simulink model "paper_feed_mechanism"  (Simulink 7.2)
settings: Solver=FixedStepDiscrete  SolverMode=SingleTasking  StartTime=0  StopTime=5  FixedStep=0.01  RelTol=1e-3
undefined symbols (not defined in the file or in its folder): Enum, ErrorCodeEnum, FeedModeEnum, sigbuilder_block

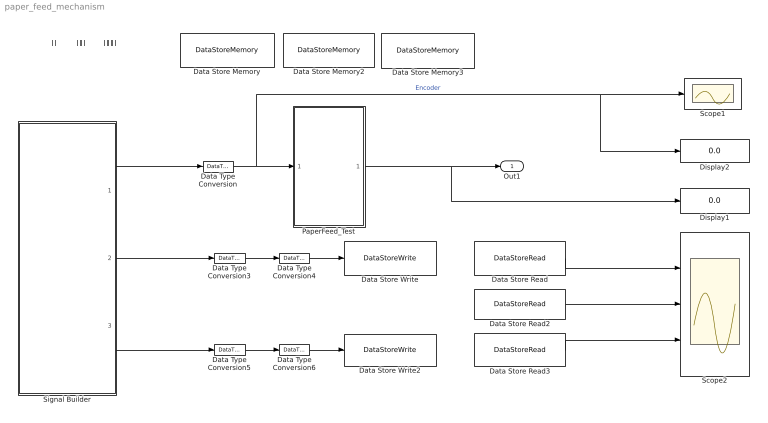
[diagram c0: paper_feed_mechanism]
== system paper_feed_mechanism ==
  note: 単体検証用モデル （給排紙機構）
  Data Store Memory : DataStoreMemory  DataStoreName=ControlMode  ReadBeforeWriteMsg=warning  WriteAfterWriteMsg=warning  WriteAfterReadMsg=warning  InitialValue=ControlModeEnum.IDLE  DataType=Specify via dialog  OutDataType=Enum: ControlModeEnum  OutDataTypeStr=Enum: ControlModeEnum
  Data Store Memory2 : DataStoreMemory  DataStoreName=FeedMode  ReadBeforeWriteMsg=warning  WriteAfterWriteMsg=warning  WriteAfterReadMsg=warning  InitialValue=FeedModeEnum.FEED_IDLE  DataType=Specify via dialog  OutDataType=Enum: FeedModeEnum  OutDataTypeStr=Enum: FeedModeEnum
  Data Store Memory3 : DataStoreMemory  Orientation=left  DataStoreName=ErrorCode  ReadBeforeWriteMsg=warning  WriteAfterWriteMsg=warning  WriteAfterReadMsg=warning  InitialValue=ErrorCodeEnum.NO_ERROR  DataType=Specify via dialog  OutDataType=Enum: ErrorCodeEnum  OutDataTypeStr=Enum: ErrorCodeEnum
  Data Store Read : DataStoreRead  DataStoreName=ControlMode  SampleTime=-1
  Data Store Read2 : DataStoreRead  DataStoreName=FeedMode  SampleTime=-1
  Data Store Read3 : DataStoreRead  DataStoreName=ErrorCode  SampleTime=-1
  Data Store Write : DataStoreWrite  DataStoreName=ControlMode  SampleTime=-1
  Data Store Write2 : DataStoreWrite  DataStoreName=FeedMode  SampleTime=-1
  Data Type Conversion : DataTypeConversion  OutDataTypeMode=int32  OutDataType=sfix(16)  OutScaling=2^0  OutDataTypeStr=int32
  Data Type Conversion3 : DataTypeConversion  OutDataTypeMode=int8  OutDataType=sfix(16)  OutScaling=2^0  OutDataTypeStr=int8
  Data Type Conversion4 : DataTypeConversion  OutDataType=sfix(16)  OutScaling=2^0
  Data Type Conversion5 : DataTypeConversion  OutDataTypeMode=int8  OutDataType=sfix(16)  OutScaling=2^0  OutDataTypeStr=int8
  Data Type Conversion6 : DataTypeConversion  OutDataType=sfix(16)  OutScaling=2^0
  Display1 : Display
  Display2 : Display
  PaperFeed_Test : Subsystem
  Scope1 : Scope
  Scope2 : Scope  NumInputPorts=3
  Signal Builder : Subsystem  Tag=STV Subsys  LoadFcn=sigbuilder_block('load');  StartFcn=sigbuilder_block('start');  StopFcn=sigbuilder_block('stop');  ClipboardFcn=sigbuilder_block('clipboard');
  Out1 : Outport  OutDataType=sfix(16)  OutScaling=2^0
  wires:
  Data Store Read2/1 -> Scope2/2
  Data Store Read3/1 -> Scope2/3
  Data Store Read/1 -> Scope2/1
  Signal Builder/1(Encoder) -> Data Type Conversion/1
  Data Type Conversion/1 -> PaperFeed_Test/1(Encoder), Scope1/1, Display2/1  "Encoder"
  Data Type Conversion3/1 -> Data Type Conversion4/1
  Data Type Conversion5/1 -> Data Type Conversion6/1
  Data Type Conversion4/1 -> Data Store Write/1
  Data Type Conversion6/1 -> Data Store Write2/1
  Signal Builder/2(ControlMode) -> Data Type Conversion3/1
  Signal Builder/3(FeedMode) -> Data Type Conversion5/1
  PaperFeed_Test/1(PWM) -> Out1/1, Display1/1

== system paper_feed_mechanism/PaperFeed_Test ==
  note: コード生成用モデル
  Encoder : Inport  OutDataType=sfix(16)  OutScaling=2^0
  Paper_Feed : Subsystem  TreatAsAtomicUnit=on
  PWM : Outport  OutDataType=sfix(16)  OutScaling=2^0
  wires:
  Encoder/1 -> Paper_Feed/1(Encoder)
  Paper_Feed/1(PWM) -> PWM/1

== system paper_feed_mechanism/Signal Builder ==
  Demux : Demux  Tag=STV Demux  Outputs=3
  FromWs : FromWorkspace  Tag=STV FromWs  VariableName=tuvar  SigBuilderData=DataTag5  VnvData=DataTag6
  Encoder : Outport  Tag=STV Outport
  ControlMode : Outport  Tag=STV Outport  Port=2
  FeedMode : Outport  Tag=STV Outport  Port=3
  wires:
  FromWs/1 -> Demux/1
  Demux/1 -> Encoder/1
  Demux/2 -> ControlMode/1
  Demux/3 -> FeedMode/1

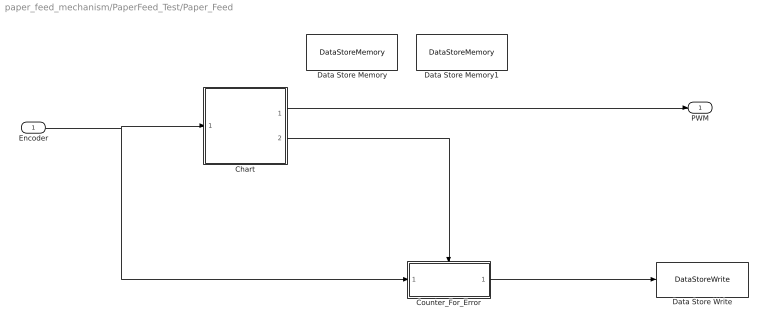
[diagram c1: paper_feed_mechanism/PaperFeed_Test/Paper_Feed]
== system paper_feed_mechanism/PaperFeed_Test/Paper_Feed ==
  Encoder : Inport  OutDataType=sfix(16)  OutScaling=2^0
  Chart : Stateflow chart
  Counter_For_Error : Subsystem  TreatAsAtomicUnit=on
  Data Store Memory : DataStoreMemory  DataStoreName=ROTOR_FLAG  ReadBeforeWriteMsg=warning  WriteAfterWriteMsg=warning  WriteAfterReadMsg=warning  DataType=boolean  OutDataType=sfix(16)  OutScaling=2^0  OutDataTypeStr=boolean
  Data Store Memory1 : DataStoreMemory  DataStoreName=ROTOR_INIT  ReadBeforeWriteMsg=warning  WriteAfterWriteMsg=warning  WriteAfterReadMsg=warning  DataType=int32  OutDataType=sfix(16)  OutScaling=2^0  OutDataTypeStr=int32
  Data Store Write : DataStoreWrite  DataStoreName=ErrorCode  SampleTime=-1
  PWM : Outport  OutDataType=sfix(16)  OutScaling=2^0
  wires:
  Chart/1(PWM) -> PWM/1
  Encoder/1 -> Chart/1(Encoder), Counter_For_Error/1(Encoder)
  Chart/2(ErrDetect) -> Counter_For_Error/Enable
  Counter_For_Error/1(ErrorCode) -> Data Store Write/1

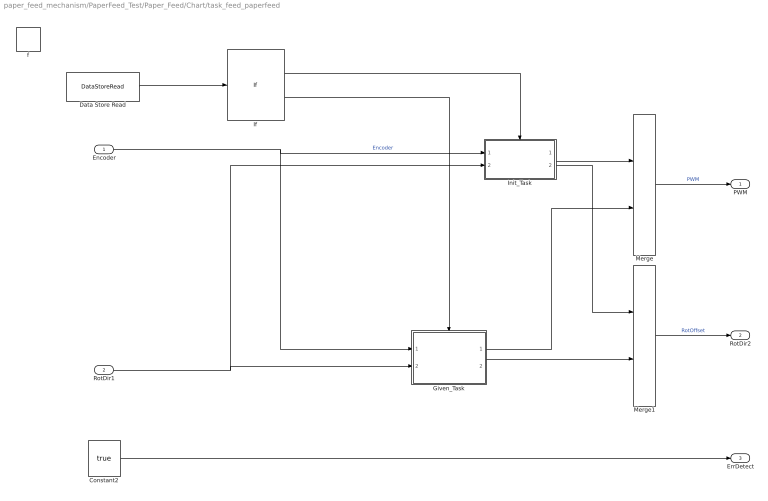
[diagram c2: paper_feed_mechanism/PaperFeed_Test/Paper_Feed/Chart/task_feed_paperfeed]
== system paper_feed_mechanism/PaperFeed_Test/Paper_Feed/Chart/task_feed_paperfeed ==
  Encoder : Inport  OutDataType=sfix(16)  OutScaling=2^0
  RotDir1 : Inport  Port=2  DataType=boolean  OutDataTypeStr=boolean
  f : TriggerPort  TriggerType=function-call  StatesWhenEnabling=reset
  Constant2 : Constant  Value=true  OutDataTypeMode=boolean  OutDataType=sfix(16)  OutScaling=2^0  OutDataTypeStr=boolean  SampleTime=-1
  Data Store Read : DataStoreRead  DataStoreName=ROTOR_FLAG  SampleTime=-1
  Given_Task : Subsystem  TreatAsAtomicUnit=on
  If : If  IfExpression=~u1
  Init_Task : Subsystem  TreatAsAtomicUnit=on
  Merge : Merge
  Merge1 : Merge
  PWM : Outport  OutDataType=sfix(16)  OutScaling=2^0
  RotDir2 : Outport  Port=2
  ErrDetect : Outport  Port=3  InitialOutput=0
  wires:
  Data Store Read/1 -> If/1
  If/1 -> Init_Task/Action
  If/2 -> Given_Task/Action
  Encoder/1 -> Init_Task/1(Encoder), Given_Task/1(Encoder)  "Encoder"
  Init_Task/1(PWM) -> Merge/1
  Merge/1 -> PWM/1  "PWM"
  RotDir1/1 -> Given_Task/2(RotOffset), Init_Task/2(RotOffset)
  Merge1/1 -> RotDir2/1  "RotOffset"
  Given_Task/2(RotOffset1) -> Merge1/2
  Given_Task/1(PWM) -> Merge/2
  Init_Task/2(RotOffset1) -> Merge1/1
  Constant2/1 -> ErrDetect/1

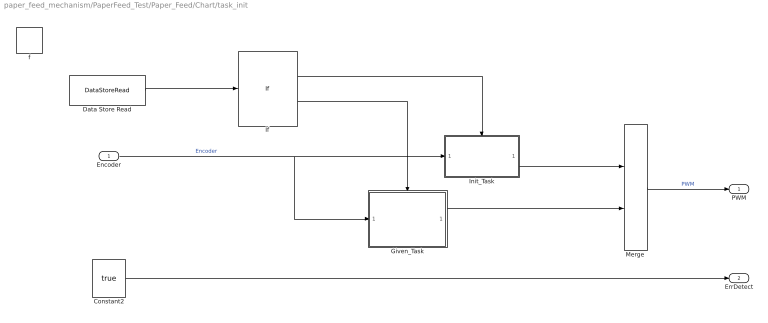
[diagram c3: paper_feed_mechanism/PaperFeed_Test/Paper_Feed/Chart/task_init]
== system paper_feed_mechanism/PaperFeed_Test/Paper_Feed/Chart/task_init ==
  Encoder : Inport  OutDataType=sfix(16)  OutScaling=2^0
  f : TriggerPort  TriggerType=function-call  StatesWhenEnabling=reset
  Constant2 : Constant  Value=true  OutDataTypeMode=boolean  OutDataType=sfix(16)  OutScaling=2^0  OutDataTypeStr=boolean  SampleTime=-1
  Data Store Read : DataStoreRead  DataStoreName=ROTOR_FLAG  SampleTime=-1
  Given_Task : Subsystem  TreatAsAtomicUnit=on
  If : If  IfExpression=~u1
  Init_Task : Subsystem  TreatAsAtomicUnit=on
  Merge : Merge
  PWM : Outport
  ErrDetect : Outport  Port=2  InitialOutput=0
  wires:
  Data Store Read/1 -> If/1
  If/1 -> Init_Task/Action
  If/2 -> Given_Task/Action
  Encoder/1 -> Init_Task/1(Encoder), Given_Task/1(Encoder)  "Encoder"
  Init_Task/1(PWM) -> Merge/1
  Merge/1 -> PWM/1  "PWM"
  Given_Task/1(PWM) -> Merge/2
  Constant2/1 -> ErrDetect/1

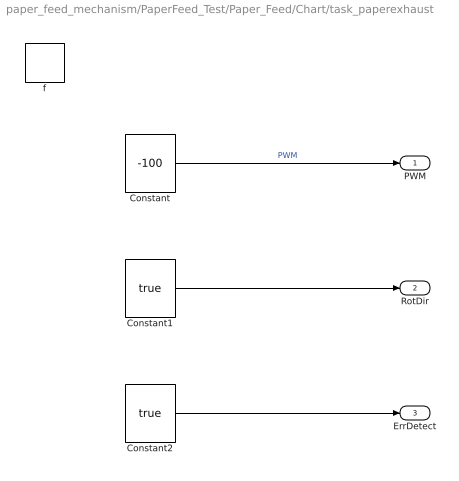
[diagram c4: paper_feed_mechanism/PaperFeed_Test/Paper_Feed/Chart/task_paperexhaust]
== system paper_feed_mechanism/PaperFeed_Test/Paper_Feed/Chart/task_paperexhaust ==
  f : TriggerPort  TriggerType=function-call  StatesWhenEnabling=reset
  Constant : Constant  Value=-100  OutDataTypeMode=int8  OutDataType=sfix(16)  OutScaling=2^0  OutDataTypeStr=int8  SampleTime=-1
  Constant1 : Constant  Value=true  OutDataTypeMode=boolean  OutDataType=sfix(16)  OutScaling=2^0  OutDataTypeStr=boolean  SampleTime=-1
  Constant2 : Constant  Value=true  OutDataTypeMode=boolean  OutDataType=sfix(16)  OutScaling=2^0  OutDataTypeStr=boolean  SampleTime=-1
  PWM : Outport  OutDataType=sfix(16)  OutScaling=2^0  InitialOutput=0
  RotDir : Outport  Port=2  InitialOutput=0
  ErrDetect : Outport  Port=3  InitialOutput=0
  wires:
  Constant/1 -> PWM/1  "PWM"
  Constant1/1 -> RotDir/1
  Constant2/1 -> ErrDetect/1

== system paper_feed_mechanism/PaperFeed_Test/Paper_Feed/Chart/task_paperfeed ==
  f : TriggerPort  TriggerType=function-call  StatesWhenEnabling=reset
  Constant : Constant  Value=100  OutDataTypeMode=int8  OutDataType=sfix(16)  OutScaling=2^0  OutDataTypeStr=int8  SampleTime=-1
  Constant1 : Constant  Value=false  OutDataTypeMode=boolean  OutDataType=sfix(16)  OutScaling=2^0  OutDataTypeStr=boolean  SampleTime=-1
  Constant2 : Constant  Value=true  OutDataTypeMode=boolean  OutDataType=sfix(16)  OutScaling=2^0  OutDataTypeStr=boolean  SampleTime=-1
  PWM : Outport  OutDataType=sfix(16)  OutScaling=2^0  InitialOutput=0
  RotDir : Outport  Port=2  InitialOutput=0
  ErrDetect : Outport  Port=3  InitialOutput=0
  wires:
  Constant/1 -> PWM/1  "PWM"
  Constant1/1 -> RotDir/1
  Constant2/1 -> ErrDetect/1

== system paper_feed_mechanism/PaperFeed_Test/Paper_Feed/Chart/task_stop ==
  f : TriggerPort  TriggerType=function-call  StatesWhenEnabling=reset
  Constant : Constant  Value=0  OutDataTypeMode=int8  OutDataType=sfix(16)  OutScaling=2^0  OutDataTypeStr=int8  SampleTime=-1
  Constant2 : Constant  Value=false  OutDataTypeMode=boolean  OutDataType=sfix(16)  OutScaling=2^0  OutDataTypeStr=boolean  SampleTime=-1
  PWM : Outport  OutDataType=sfix(16)  OutScaling=2^0  InitialOutput=0
  ErrDetect : Outport  Port=2  InitialOutput=0
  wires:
  Constant/1 -> PWM/1  "PWM"
  Constant2/1 -> ErrDetect/1

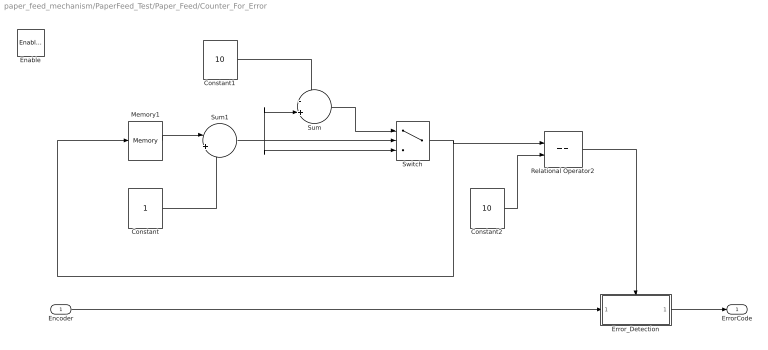
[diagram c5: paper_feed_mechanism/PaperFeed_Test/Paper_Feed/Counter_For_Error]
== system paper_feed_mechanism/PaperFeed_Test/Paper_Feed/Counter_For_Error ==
  Encoder : Inport  OutDataType=sfix(16)  OutScaling=2^0
  Enable : EnablePort  StatesWhenEnabling=reset
  Constant : Constant  OutDataTypeMode=uint8  OutDataType=sfix(16)  OutScaling=2^0  OutDataTypeStr=uint8  SampleTime=-1
  Constant1 : Constant  Value=10  OutDataTypeMode=uint8  OutDataType=sfix(16)  OutScaling=2^0  OutDataTypeStr=uint8  SampleTime=-1
  Constant2 : Constant  Value=10  OutDataTypeMode=uint8  OutDataType=sfix(16)  OutScaling=2^0  OutDataTypeStr=uint8  SampleTime=-1
  Error_Detection : Subsystem  TreatAsAtomicUnit=on
  Memory1 : Memory  InheritSampleTime=on
  Relational Operator2 : RelationalOperator  Operator===  LogicOutDataTypeMode=boolean  OutDataTypeStr=boolean
  Sum : Sum  Inputs=-+|  OutDataType=sfix(16)  OutScaling=2^0
  Sum1 : Sum  Inputs=|++  OutDataType=sfix(16)  OutScaling=2^0
  Switch : Switch  Criteria=u2 > Threshold  Threshold=10  OutDataTypeMode=uint8  OutDataType=sfix(16)  OutScaling=2^0  OutDataTypeStr=uint8
  ErrorCode : Outport  OutDataType=sfix(16)  OutScaling=2^0  InitialOutput=ErrorCodeEnum.NO_ERROR
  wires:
  Constant/1 -> Sum1/2
  Encoder/1 -> Error_Detection/1(Encoder)
  Error_Detection/1(ErrorCode) -> ErrorCode/1
  Relational Operator2/1 -> Error_Detection/Trigger
  Memory1/1 -> Sum1/1
  Switch/1 -> Relational Operator2/1, Memory1/1
  Constant1/1 -> Sum/1
  Sum1/1 -> Switch/2, Sum/2, Switch/3
  Sum/1 -> Switch/1
  Constant2/1 -> Relational Operator2/2

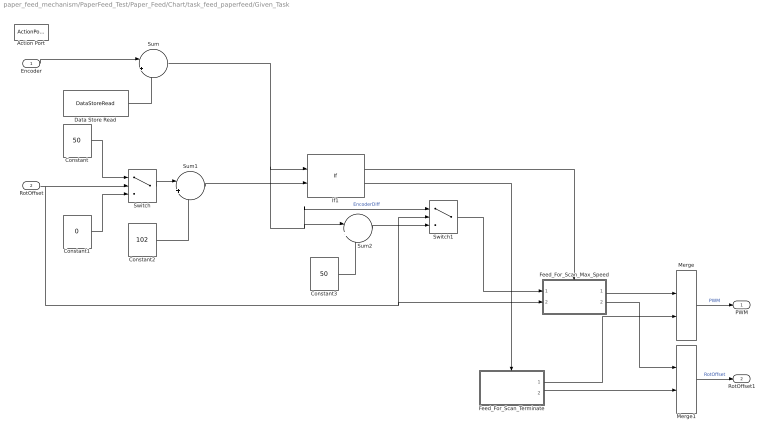
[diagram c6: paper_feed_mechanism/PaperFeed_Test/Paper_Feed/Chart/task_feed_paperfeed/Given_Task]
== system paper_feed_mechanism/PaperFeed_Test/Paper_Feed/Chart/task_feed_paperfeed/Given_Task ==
  Encoder : Inport  OutDataType=sfix(16)  OutScaling=2^0
  RotOffset : Inport  Port=2  OutDataType=sfix(16)  OutScaling=2^0
  Action Port : ActionPort  ActionType=else
  Constant : Constant  Value=50  OutDataTypeMode=int32  OutDataType=sfix(16)  OutScaling=2^0  OutDataTypeStr=int32  SampleTime=-1
  Constant1 : Constant  Value=0  OutDataTypeMode=int32  OutDataType=sfix(16)  OutScaling=2^0  OutDataTypeStr=int32  SampleTime=-1
  Constant2 : Constant  Value=102  OutDataTypeMode=int32  OutDataType=sfix(16)  OutScaling=2^0  OutDataTypeStr=int32  SampleTime=-1
  Constant3 : Constant  Value=50  OutDataTypeMode=int32  OutDataType=sfix(16)  OutScaling=2^0  OutDataTypeStr=int32  SampleTime=-1
  Data Store Read : DataStoreRead  DataStoreName=ROTOR_INIT  SampleTime=-1
  Feed_For_Scan_Max_Speed : Subsystem  TreatAsAtomicUnit=on
  Feed_For_Scan_Terminate : Subsystem  TreatAsAtomicUnit=on
  If1 : If  NumInputs=2  IfExpression=u1 < u2
  Merge : Merge
  Merge1 : Merge
  Sum : Sum  Inputs=|+-  OutDataType=sfix(16)  OutScaling=2^0
  Sum1 : Sum  Inputs=|++  OutDataType=sfix(16)  OutScaling=2^0
  Sum2 : Sum  Inputs=|++  OutDataType=sfix(16)  OutScaling=2^0
  Switch : Switch  Criteria=u2 ~= 0  OutDataType=sfix(16)  OutScaling=2^0
  Switch1 : Switch  Criteria=u2 ~= 0  OutDataType=sfix(16)  OutScaling=2^0
  PWM : Outport  OutDataType=sfix(16)  OutScaling=2^0
  RotOffset1 : Outport  Port=2  OutDataType=sfix(16)  OutScaling=2^0
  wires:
  Data Store Read/1 -> Sum/2
  Sum/1 -> If1/1, Sum2/1, Switch1/1  "EncoderDiff"
  Encoder/1 -> Sum/1
  If1/1 -> Feed_For_Scan_Max_Speed/Action
  If1/2 -> Feed_For_Scan_Terminate/Action
  Merge/1 -> PWM/1  "PWM"
  RotOffset/1 -> Switch/2, Feed_For_Scan_Max_Speed/2(RotOffset), Switch1/2
  Switch/1 -> Sum1/1
  Constant2/1 -> Sum1/2
  Merge1/1 -> RotOffset1/1  "RotOffset"
  Constant/1 -> Switch/1
  Constant1/1 -> Switch/3
  Feed_For_Scan_Max_Speed/1(PWM) -> Merge/1
  Feed_For_Scan_Terminate/1(PWM) -> Merge/2
  Feed_For_Scan_Max_Speed/2(RotOffset1) -> Merge1/1
  Feed_For_Scan_Terminate/2(RotOffset) -> Merge1/2
  Sum1/1 -> If1/2
  Constant3/1 -> Sum2/2
  Switch1/1 -> Feed_For_Scan_Max_Speed/1(EncoderDiff)
  Sum2/1 -> Switch1/3

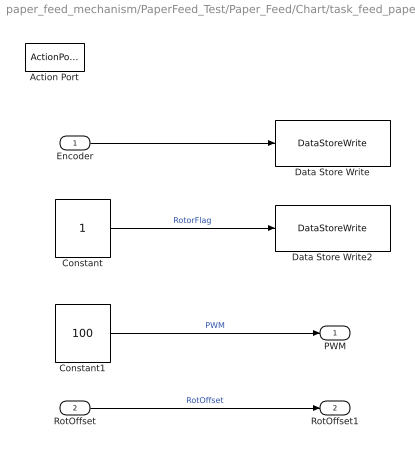
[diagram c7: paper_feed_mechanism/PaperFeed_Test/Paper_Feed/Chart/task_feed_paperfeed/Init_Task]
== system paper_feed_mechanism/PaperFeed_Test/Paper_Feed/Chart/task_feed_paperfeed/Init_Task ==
  Encoder : Inport  OutDataType=sfix(16)  OutScaling=2^0
  RotOffset : Inport  Port=2  OutDataType=sfix(16)  OutScaling=2^0
  Action Port : ActionPort  ActionType=then
  Constant : Constant  OutDataTypeMode=boolean  OutDataType=sfix(16)  OutScaling=2^0  OutDataTypeStr=boolean  SampleTime=-1
  Constant1 : Constant  Value=100  OutDataTypeMode=int8  OutDataType=sfix(16)  OutScaling=2^0  OutDataTypeStr=int8  SampleTime=-1
  Data Store Write : DataStoreWrite  DataStoreName=ROTOR_INIT  SampleTime=-1
  Data Store Write2 : DataStoreWrite  DataStoreName=ROTOR_FLAG  SampleTime=-1
  PWM : Outport  OutDataType=sfix(16)  OutScaling=2^0  InitialOutput=100
  RotOffset1 : Outport  Port=2
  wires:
  Encoder/1 -> Data Store Write/1
  Constant/1 -> Data Store Write2/1  "RotorFlag"
  Constant1/1 -> PWM/1  "PWM"
  RotOffset/1 -> RotOffset1/1  "RotOffset"

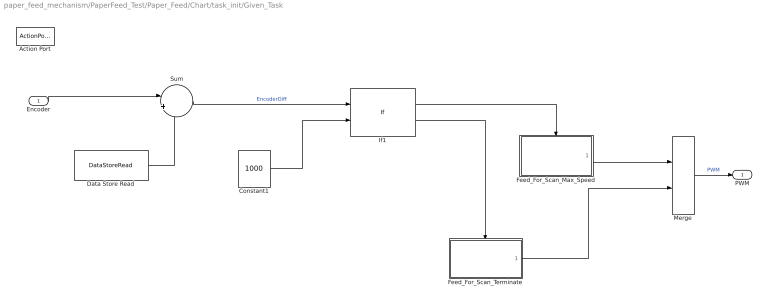
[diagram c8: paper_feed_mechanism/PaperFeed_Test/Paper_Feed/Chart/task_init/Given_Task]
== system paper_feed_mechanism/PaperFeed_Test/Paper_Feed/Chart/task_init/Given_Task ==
  Encoder : Inport  OutDataType=sfix(16)  OutScaling=2^0
  Action Port : ActionPort  ActionType=else
  Constant1 : Constant  Value=1000  OutDataTypeMode=int32  OutDataType=sfix(16)  OutScaling=2^0  OutDataTypeStr=int32  SampleTime=-1
  Data Store Read : DataStoreRead  DataStoreName=ROTOR_INIT  SampleTime=-1
  Feed_For_Scan_Max_Speed : Subsystem  TreatAsAtomicUnit=on
  Feed_For_Scan_Terminate : Subsystem  TreatAsAtomicUnit=on
  If1 : If  NumInputs=2  IfExpression=u1 < u2
  Merge : Merge
  Sum : Sum  Inputs=|+-  OutDataType=sfix(16)  OutScaling=2^0
  PWM : Outport  OutDataType=sfix(16)  OutScaling=2^0
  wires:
  Data Store Read/1 -> Sum/2
  Sum/1 -> If1/1  "EncoderDiff"
  Encoder/1 -> Sum/1
  If1/1 -> Feed_For_Scan_Max_Speed/Action
  If1/2 -> Feed_For_Scan_Terminate/Action
  Merge/1 -> PWM/1  "PWM"
  Feed_For_Scan_Max_Speed/1(PWM) -> Merge/1
  Constant1/1 -> If1/2
  Feed_For_Scan_Terminate/1(PWM) -> Merge/2

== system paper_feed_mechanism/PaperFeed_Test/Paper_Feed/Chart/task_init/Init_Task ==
  Encoder : Inport  OutDataType=sfix(16)  OutScaling=2^0
  Action Port : ActionPort  ActionType=then
  Constant : Constant  OutDataTypeMode=boolean  OutDataType=sfix(16)  OutScaling=2^0  OutDataTypeStr=boolean  SampleTime=-1
  Constant1 : Constant  Value=100  OutDataTypeMode=int8  OutDataType=sfix(16)  OutScaling=2^0  OutDataTypeStr=int8  SampleTime=-1
  Data Store Write : DataStoreWrite  DataStoreName=ROTOR_INIT  SampleTime=-1
  Data Store Write2 : DataStoreWrite  DataStoreName=ROTOR_FLAG  SampleTime=-1
  PWM : Outport  OutDataType=sfix(16)  OutScaling=2^0  InitialOutput=100
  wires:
  Constant/1 -> Data Store Write2/1  "RotorFlag"
  Constant1/1 -> PWM/1  "PWM"
  Encoder/1 -> Data Store Write/1

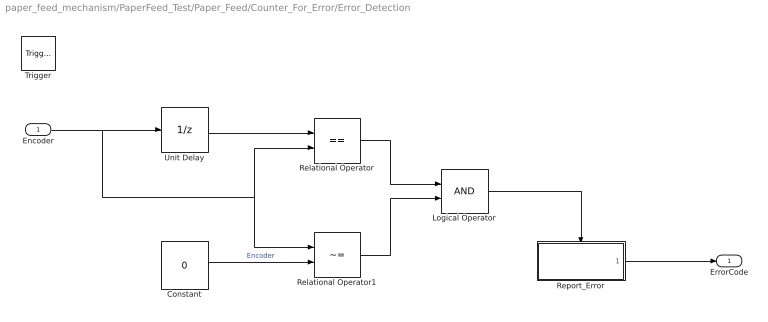
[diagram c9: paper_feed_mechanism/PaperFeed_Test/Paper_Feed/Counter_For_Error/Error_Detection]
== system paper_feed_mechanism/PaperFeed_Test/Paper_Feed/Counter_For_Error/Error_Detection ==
  Encoder : Inport  OutDataType=sfix(16)  OutScaling=2^0
  Trigger : TriggerPort
  Constant : Constant  Value=0  OutDataTypeMode=int8  OutDataType=sfix(16)  OutScaling=2^0  OutDataTypeStr=int8  SampleTime=-1
  Logical Operator : Logic  AllPortsSameDT=off  OutDataTypeMode=boolean  OutDataTypeStr=boolean
  Relational Operator : RelationalOperator  Operator===  LogicOutDataTypeMode=boolean  OutDataTypeStr=boolean
  Relational Operator1 : RelationalOperator  Operator=~=  LogicOutDataTypeMode=boolean  OutDataTypeStr=boolean
  Report_Error : Subsystem  TreatAsAtomicUnit=on
  Unit Delay : UnitDelay  SampleTime=-1
  ErrorCode : Outport  OutDataType=sfix(16)  OutScaling=2^0
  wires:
  Report_Error/1(ErrorCode) -> ErrorCode/1
  Logical Operator/1 -> Report_Error/Enable
  Unit Delay/1 -> Relational Operator/1
  Relational Operator1/1 -> Logical Operator/2
  Relational Operator/1 -> Logical Operator/1
  Encoder/1 -> Unit Delay/1, Relational Operator1/1, Relational Operator/2
  Constant/1 -> Relational Operator1/2  "Encoder"

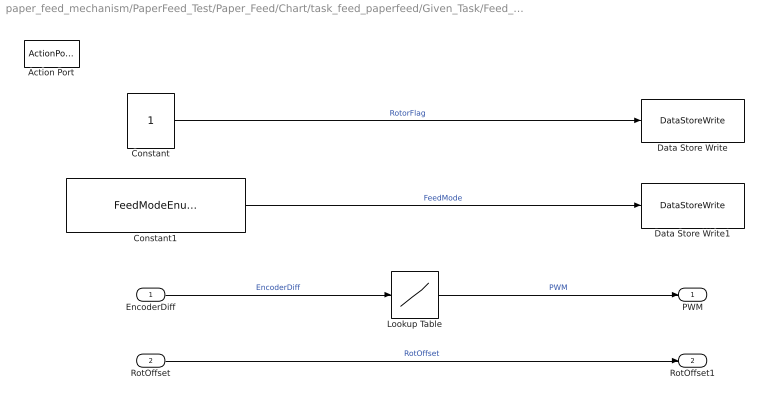
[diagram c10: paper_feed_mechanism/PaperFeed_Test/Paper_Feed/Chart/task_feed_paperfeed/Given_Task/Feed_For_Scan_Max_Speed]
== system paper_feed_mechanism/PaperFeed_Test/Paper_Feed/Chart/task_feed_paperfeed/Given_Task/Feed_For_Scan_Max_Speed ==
  EncoderDiff : Inport  OutDataType=sfix(16)  OutScaling=2^0
  RotOffset : Inport  Port=2  OutDataType=sfix(16)  OutScaling=2^0
  Action Port : ActionPort  ActionType=then
  Constant : Constant  OutDataTypeMode=boolean  OutDataType=sfix(16)  OutScaling=2^0  OutDataTypeStr=boolean  SampleTime=-1
  Constant1 : Constant  Value=FeedModeEnum.FEED_PAPERFEED  OutDataTypeMode=Specify via dialog  OutDataType=Enum: FeedModeEnum  ConRadixGroup=Best Precision: Vector-wise  OutDataTypeStr=Enum: FeedModeEnum  SampleTime=-1
  Data Store Write : DataStoreWrite  DataStoreName=ROTOR_FLAG  SampleTime=-1
  Data Store Write1 : DataStoreWrite  DataStoreName=FeedMode  SampleTime=-1
  Lookup Table : Lookup  InputValues=int32(0:10:150)  Table=int8([100 100 100 100 100 100 77 45 35 25 18 13 10 8 4 4]);  LookUpMeth=Use Input Nearest  OutDataTypeMode=int8  OutDataType=sfix(16)  OutScaling=2^0  OutDataTypeStr=int8
  PWM : Outport  OutDataType=sfix(16)  OutScaling=2^0  InitialOutput=100
  RotOffset1 : Outport  Port=2
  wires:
  Constant/1 -> Data Store Write/1  "RotorFlag"
  Constant1/1 -> Data Store Write1/1  "FeedMode"
  EncoderDiff/1 -> Lookup Table/1  "EncoderDiff"
  Lookup Table/1 -> PWM/1  "PWM"
  RotOffset/1 -> RotOffset1/1  "RotOffset"

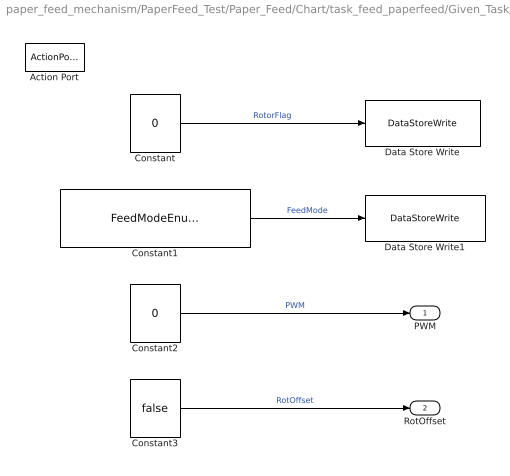
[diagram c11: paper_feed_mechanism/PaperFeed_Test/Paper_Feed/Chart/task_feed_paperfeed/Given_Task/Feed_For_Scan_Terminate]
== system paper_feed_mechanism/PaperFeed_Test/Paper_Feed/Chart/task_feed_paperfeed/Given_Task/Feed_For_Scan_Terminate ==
  Action Port : ActionPort  ActionType=else
  Constant : Constant  Value=0  OutDataTypeMode=boolean  OutDataType=sfix(16)  OutScaling=2^0  OutDataTypeStr=boolean  SampleTime=-1
  Constant1 : Constant  Value=FeedModeEnum.FEED_IDLE  OutDataTypeMode=Specify via dialog  OutDataType=Enum: FeedModeEnum  ConRadixGroup=Best Precision: Vector-wise  OutDataTypeStr=Enum: FeedModeEnum  SampleTime=-1
  Constant2 : Constant  Value=0  OutDataTypeMode=int8  OutDataType=sfix(16)  OutScaling=2^0  OutDataTypeStr=int8  SampleTime=-1
  Constant3 : Constant  Value=false  OutDataTypeMode=boolean  OutDataType=sfix(16)  OutScaling=2^0  OutDataTypeStr=boolean  SampleTime=-1
  Data Store Write : DataStoreWrite  DataStoreName=ROTOR_FLAG  SampleTime=-1
  Data Store Write1 : DataStoreWrite  DataStoreName=FeedMode  SampleTime=-1
  PWM : Outport  OutDataType=sfix(16)  OutScaling=2^0  InitialOutput=0
  RotOffset : Outport  Port=2  InitialOutput=0
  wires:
  Constant/1 -> Data Store Write/1  "RotorFlag"
  Constant1/1 -> Data Store Write1/1  "FeedMode"
  Constant2/1 -> PWM/1  "PWM"
  Constant3/1 -> RotOffset/1  "RotOffset"

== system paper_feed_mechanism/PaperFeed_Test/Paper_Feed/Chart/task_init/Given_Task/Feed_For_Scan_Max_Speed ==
  Action Port : ActionPort  ActionType=then
  Constant : Constant  OutDataTypeMode=boolean  OutDataType=sfix(16)  OutScaling=2^0  OutDataTypeStr=boolean  SampleTime=-1
  Constant1 : Constant  Value=100  OutDataTypeMode=int8  OutDataType=sfix(16)  OutScaling=2^0  OutDataTypeStr=int8  SampleTime=-1
  Constant2 : Constant  Value=FeedModeEnum.FEED_INIT  OutDataTypeMode=Specify via dialog  OutDataType=Enum: FeedModeEnum  ConRadixGroup=Best Precision: Vector-wise  OutDataTypeStr=Enum: FeedModeEnum  SampleTime=-1
  Data Store Write : DataStoreWrite  DataStoreName=ROTOR_FLAG  SampleTime=-1
  Data Store Write1 : DataStoreWrite  DataStoreName=FeedMode  SampleTime=-1
  PWM : Outport  OutDataType=sfix(16)  OutScaling=2^0  InitialOutput=100
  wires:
  Constant/1 -> Data Store Write/1  "RotorFlag"
  Constant1/1 -> PWM/1  "PWM"
  Constant2/1 -> Data Store Write1/1  "FeedMode"

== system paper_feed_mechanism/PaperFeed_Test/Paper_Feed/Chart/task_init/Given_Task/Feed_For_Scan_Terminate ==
  Action Port : ActionPort  ActionType=else
  Constant : Constant  Value=0  OutDataTypeMode=boolean  OutDataType=sfix(16)  OutScaling=2^0  OutDataTypeStr=boolean  SampleTime=-1
  Constant1 : Constant  Value=0  OutDataTypeMode=int8  OutDataType=sfix(16)  OutScaling=2^0  OutDataTypeStr=int8  SampleTime=-1
  Constant2 : Constant  Value=FeedModeEnum.FEED_IDLE  OutDataTypeMode=Specify via dialog  OutDataType=Enum: FeedModeEnum  ConRadixGroup=Best Precision: Vector-wise  OutDataTypeStr=Enum: FeedModeEnum  SampleTime=-1
  Data Store Write : DataStoreWrite  DataStoreName=ROTOR_FLAG  SampleTime=-1
  Data Store Write1 : DataStoreWrite  DataStoreName=FeedMode  SampleTime=-1
  PWM : Outport  OutDataType=sfix(16)  OutScaling=2^0  InitialOutput=100
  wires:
  Constant/1 -> Data Store Write/1  "RotorFlag"
  Constant1/1 -> PWM/1  "PWM"
  Constant2/1 -> Data Store Write1/1  "FeedMode"

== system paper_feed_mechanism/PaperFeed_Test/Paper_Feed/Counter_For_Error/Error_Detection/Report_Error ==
  Enable : EnablePort
  Constant : Constant  Value=ErrorCodeEnum.ERROR_002  OutDataTypeMode=Specify via dialog  OutDataType=Enum:ErrorCodeEnum  ConRadixGroup=Best Precision: Vector-wise  OutDataTypeStr=Enum:ErrorCodeEnum  SampleTime=-1
  ErrorCode : Outport  OutDataType=sfix(16)  OutScaling=2^0
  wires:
  Constant/1 -> ErrorCode/1  "ErrorCode"

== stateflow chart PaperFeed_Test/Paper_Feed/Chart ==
  state [PWM,RotDir,ErrDetect] = task_paperfeed [function]
  state [PWM,RotDir,ErrDetect] = task_paperexhaust [function]
  state [PWM,ErrDetect] = task_stop [function]
  state [PWM,RotDir2,ErrDetect] = task_feed_paperfeed(Encoder,RotDir1) [function]
  state [PWM,ErrDetect] = task_init(Encoder) [function]
  (junction 10) -> (junction 14)
  (junction 8) -> (junction 12)
  (junction 13) -> (junction 15) : {[PWM, ErrDetect] = task_stop();}
  (junction 18) -> (junction 10)
  (junction 17) -> (junction 12) : {[PWM, RotDir, ErrDetect]= task_paperexhaust();}
  (junction 14) -> (junction 13) : [ControlMode == IDLE]
  (junction 9) -> (junction 22) : [FeedMode == FEED_PAPERFEED]
  (junction 10) -> (junction 17) : [ControlMode == PAPEREXHAUST]
  (junction 11) -> (junction 8) : {[PWM, RotDir, ErrDetect] = task_paperfeed();}
  (default) -> (junction 27)
  (junction 9) -> (junction 21) : {[PWM, ErrDetect] = task_stop();}
  (junction 18) -> (junction 11) : [ControlMode == PAPERFEED]
  (junction 24) -> (junction 23) : [ControlMode == ERROR]
  (junction 12) -> (junction 15)
  (junction 21) -> (junction 19)
  (junction 20) -> (junction 21)
  (junction 22) -> (junction 20) : {[PWM, RotDir, ErrDetect] = ... task_feed_paperfeed(Encoder, RotDir);}
  (junction 14) -> (junction 24)
  (junction 15) -> (junction 16)
  (junction 23) -> (junction 16) : {[PWM, ErrDetect] = task_stop();}
  (junction 24) -> (junction 9)
  (junction 25) -> (junction 28)
  (junction 30) -> (junction 25) : {[PWM, ErrDetect] = task_init(Encoder);}
  (junction 19) -> (junction 26)
  (junction 27) -> (junction 29) : [ControlMode == INITIALIZE]
  (junction 28) -> (junction 8)
  (junction 27) -> (junction 18)
  (junction 29) -> (junction 30) : [FeedMode == FEED_INIT]
  (junction 29) -> (junction 28) : {[PWM, ErrDetect] = task_stop();}
  (junction 16) -> (junction 19)
